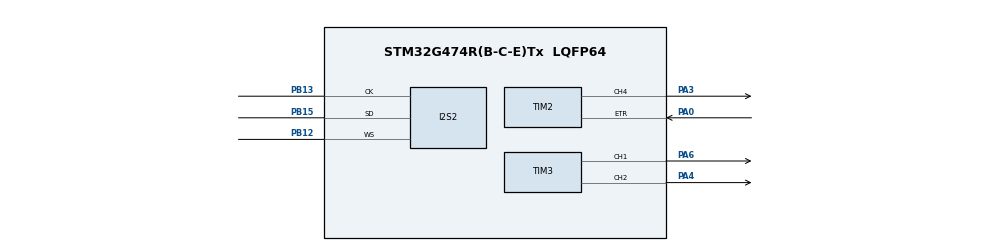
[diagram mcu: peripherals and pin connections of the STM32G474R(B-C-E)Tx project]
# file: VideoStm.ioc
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Dma.Request0=TIM3_CH1
Dma.Request1=TIM3_CH3
Dma.Request2=TIM3_CH4
Dma.Request3=SPI2_TX
Dma.SPI2_TX.3.Direction=DMA_MEMORY_TO_PERIPH
Dma.SPI2_TX.3.EventEnable=DISABLE
Dma.SPI2_TX.3.Instance=DMA1_Channel5
Dma.SPI2_TX.3.MemDataAlignment=DMA_MDATAALIGN_HALFWORD
Dma.SPI2_TX.3.MemInc=DMA_MINC_ENABLE
Dma.SPI2_TX.3.Mode=DMA_CIRCULAR
Dma.SPI2_TX.3.PeriphDataAlignment=DMA_PDATAALIGN_HALFWORD
Dma.SPI2_TX.3.PeriphInc=DMA_PINC_DISABLE
Dma.SPI2_TX.3.Polarity=HAL_DMAMUX_REQ_GEN_RISING
Dma.SPI2_TX.3.Priority=DMA_PRIORITY_HIGH
Dma.SPI2_TX.3.RequestNumber=1
Dma.SPI2_TX.3.SignalID=NONE
Dma.SPI2_TX.3.SyncEnable=DISABLE
Dma.SPI2_TX.3.SyncPolarity=HAL_DMAMUX_SYNC_NO_EVENT
Dma.SPI2_TX.3.SyncRequestNumber=1
Dma.SPI2_TX.3.SyncSignalID=NONE
Dma.TIM3_CH1.0.Direction=DMA_MEMORY_TO_PERIPH
Dma.TIM3_CH1.0.EventEnable=DISABLE
Dma.TIM3_CH1.0.Instance=DMA1_Channel6
Dma.TIM3_CH1.0.MemDataAlignment=DMA_MDATAALIGN_HALFWORD
Dma.TIM3_CH1.0.MemInc=DMA_MINC_ENABLE
Dma.TIM3_CH1.0.Mode=DMA_CIRCULAR
Dma.TIM3_CH1.0.PeriphDataAlignment=DMA_PDATAALIGN_HALFWORD
Dma.TIM3_CH1.0.PeriphInc=DMA_PINC_DISABLE
Dma.TIM3_CH1.0.Polarity=HAL_DMAMUX_REQ_GEN_RISING
Dma.TIM3_CH1.0.Priority=DMA_PRIORITY_MEDIUM
Dma.TIM3_CH1.0.RequestNumber=1
Dma.TIM3_CH1.0.SignalID=NONE
Dma.TIM3_CH1.0.SyncEnable=DISABLE
Dma.TIM3_CH1.0.SyncPolarity=HAL_DMAMUX_SYNC_NO_EVENT
Dma.TIM3_CH1.0.SyncRequestNumber=1
Dma.TIM3_CH1.0.SyncSignalID=NONE
Dma.TIM3_CH3.1.Direction=DMA_MEMORY_TO_PERIPH
Dma.TIM3_CH3.1.EventEnable=DISABLE
Dma.TIM3_CH3.1.Instance=DMA1_Channel2
Dma.TIM3_CH3.1.MemDataAlignment=DMA_MDATAALIGN_WORD
Dma.TIM3_CH3.1.MemInc=DMA_MINC_ENABLE
Dma.TIM3_CH3.1.Mode=DMA_CIRCULAR
Dma.TIM3_CH3.1.PeriphDataAlignment=DMA_PDATAALIGN_WORD
Dma.TIM3_CH3.1.PeriphInc=DMA_PINC_DISABLE
Dma.TIM3_CH3.1.Polarity=HAL_DMAMUX_REQ_GEN_RISING
Dma.TIM3_CH3.1.Priority=DMA_PRIORITY_MEDIUM
Dma.TIM3_CH3.1.RequestNumber=1
Dma.TIM3_CH3.1.SignalID=NONE
Dma.TIM3_CH3.1.SyncEnable=DISABLE
Dma.TIM3_CH3.1.SyncPolarity=HAL_DMAMUX_SYNC_NO_EVENT
Dma.TIM3_CH3.1.SyncRequestNumber=1
Dma.TIM3_CH3.1.SyncSignalID=NONE
Dma.TIM3_CH4.2.Direction=DMA_MEMORY_TO_PERIPH
Dma.TIM3_CH4.2.EventEnable=DISABLE
Dma.TIM3_CH4.2.Instance=DMA1_Channel3
Dma.TIM3_CH4.2.MemDataAlignment=DMA_MDATAALIGN_WORD
Dma.TIM3_CH4.2.MemInc=DMA_MINC_ENABLE
Dma.TIM3_CH4.2.Mode=DMA_CIRCULAR
Dma.TIM3_CH4.2.PeriphDataAlignment=DMA_PDATAALIGN_WORD
Dma.TIM3_CH4.2.PeriphInc=DMA_PINC_DISABLE
Dma.TIM3_CH4.2.Polarity=HAL_DMAMUX_REQ_GEN_RISING
Dma.TIM3_CH4.2.Priority=DMA_PRIORITY_MEDIUM
Dma.TIM3_CH4.2.RequestNumber=1
Dma.TIM3_CH4.2.SignalID=NONE
Dma.TIM3_CH4.2.SyncEnable=DISABLE
Dma.TIM3_CH4.2.SyncPolarity=HAL_DMAMUX_SYNC_NO_EVENT
Dma.TIM3_CH4.2.SyncRequestNumber=1
Dma.TIM3_CH4.2.SyncSignalID=NONE
I2S2.ErrorAudioFreq=- %
I2S2.FullDuplexMode=I2S_FULLDUPLEXMODE_DISABLE
I2S2.Instance=SPI$Index
I2S2.RealAudioFreq=- Hz
I2S2.VirtualMode=I2S_MODE_MASTER
Mcu.Family=STM32G4
Mcu.Name=STM32G474R(B-C-E)Tx
Mcu.Package=LQFP64
NVIC.DMA1_Channel2_IRQn=true\:0\:0\:false\:false\:true\:false\:true\:true
NVIC.DMA1_Channel3_IRQn=true\:0\:0\:false\:false\:true\:false\:true\:true
NVIC.DMA1_Channel5_IRQn=true\:0\:0\:false\:false\:true\:false\:true\:true
NVIC.DMA1_Channel6_IRQn=true\:0\:0\:false\:false\:true\:false\:true\:true
NVIC.PriorityGroup=NVIC_PRIORITYGROUP_4
PA0.Signal=S_TIM2_ETR
PA3.Signal=S_TIM2_CH4
PA4.Signal=S_TIM3_CH2
PA6.Signal=S_TIM3_CH1
PB12.Mode=Half_Duplex_Master
PB12.Signal=I2S2_WS
PB13.Mode=Half_Duplex_Master
PB13.Signal=I2S2_CK
PB15.Mode=Half_Duplex_Master
PB15.Signal=I2S2_SD
PF0-OSC_IN.Mode=HSE-External-Clock-Source
PF0-OSC_IN.Signal=RCC_OSC_IN
ProjectManager.HeapSize=0x200
ProjectManager.StackSize=0x400
ProjectManager.TargetToolchain=STM32CubeIDE
RCC.ADC12Freq_Value=168000000
RCC.ADC345Freq_Value=168000000
RCC.AHBFreq_Value=168000000
RCC.APB1Freq_Value=168000000
RCC.APB1TimFreq_Value=168000000
RCC.APB2Freq_Value=168000000
RCC.APB2TimFreq_Value=168000000
RCC.CortexFreq_Value=168000000
RCC.EXTERNAL_CLOCK_VALUE=12288000
RCC.HCLKFreq_Value=168000000
RCC.HSE_VALUE=8000000
RCC.HSI48_VALUE=48000000
RCC.HSI_VALUE=16000000
RCC.LSE_VALUE=32768
RCC.PLLN=42
RCC.PLLSourceVirtual=RCC_PLLSOURCE_HSE
RCC.SYSCLKFreq_VALUE=168000000
RCC.SYSCLKSource=RCC_SYSCLKSOURCE_PLLCLK
RCC.USBFreq_Value=168000000
RCC.VCOOutputFreq_Value=336000000
SH.S_TIM2_CH4.0=TIM2_CH4,PWM Generation4 CH4
SH.S_TIM2_ETR.0=TIM2_ETR,TriggerSource_ETR
SH.S_TIM3_CH1.0=TIM3_CH1,Output Compare1 CH1
SH.S_TIM3_CH2.0=TIM3_CH2,PWM Generation2 CH2
TIM2.Channel-PWM\ Generation4\ CH4=TIM_CHANNEL_4
TIM2.ClockDivision=TIM_CLOCKDIVISION_DIV2
TIM2.OCPolarity_4=TIM_OCPOLARITY_LOW
TIM2.TIM_MasterOutputTrigger=TIM_TRGO_OC4REF
TIM2.TIM_MasterSlaveMode=TIM_MASTERSLAVEMODE_ENABLE
TIM3.Channel-Output\ Compare1\ CH1=TIM_CHANNEL_1
TIM3.Channel-Output\ Compare3\ No\ Output=TIM_CHANNEL_3
TIM3.Channel-Output\ Compare4\ No\ Output=TIM_CHANNEL_4
TIM3.Channel-PWM\ Generation2\ CH2=TIM_CHANNEL_2
TIM3.OCMode_1=TIM_OCMODE_TOGGLE
TIM3.OCPolarity_1=TIM_OCPOLARITY_LOW
TIM3.OCPolarity_2=TIM_OCPOLARITY_LOW
TIM3.OCPolarity_3=TIM_OCPOLARITY_LOW
TIM3.OCPolarity_4=TIM_OCPOLARITY_LOW
TIM3.PulseNoDither_1=0xffff
TIM3.PulseNoDither_3=208
TIM3.PulseNoDither_4=208+672
VP_SYS_VS_DBSignals.Mode=DisableDeadBatterySignals
VP_TIM2_VS_ClockSourceINT.Mode=Internal
VP_TIM2_VS_ControllerModeTrigger.Mode=Trigger Mode
VP_TIM3_VS_ClockSourceINT.Mode=Internal
VP_TIM3_VS_ClockSourceITR.Mode=TriggerSource_ITR1
VP_TIM3_VS_ControllerModeTrigger.Mode=Trigger Mode
VP_TIM3_VS_no_output3.Mode=Output Compare3 No Output
VP_TIM3_VS_no_output4.Mode=Output Compare4 No Output
board=custom

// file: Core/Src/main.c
/* USER CODE BEGIN Header */
/**
  ******************************************************************************
  * @file           : main.c
  * @brief          : Main program body
  ******************************************************************************
  * @attention
  *
  * Copyright (c) 2025 STMicroelectronics.
  * All rights reserved.
  *
  * This software is licensed under terms that can be found in the LICENSE file
  * in the root directory of this software component.
  * If no LICENSE file comes with this software, it is provided AS-IS.
  *
  ******************************************************************************
  */
/* USER CODE END Header */
#include "main.h"

/* USER CODE BEGIN Includes */
#include "stm32g4xx_hal.h"
#include "video.h"
#include <stdlib.h>
#include <string.h>
#include "stdio.h"

void show(void);
/* USER CODE END Includes */

/* USER CODE BEGIN PD */
//uint16_t fullFrame[TOTAL_LINES * VID_HSIZE];

/* USER CODE END PD */

/* USER CODE BEGIN PM */
//#define DelayMs(ms)  HAL_Delay(ms)

/* USER CODE END PM */

I2S_HandleTypeDef hi2s2;
DMA_HandleTypeDef hdma_spi2_tx;

TIM_HandleTypeDef htim2;
TIM_HandleTypeDef htim3;
DMA_HandleTypeDef hdma_tim3_ch1;
DMA_HandleTypeDef hdma_tim3_ch3;
DMA_HandleTypeDef hdma_tim3_ch4;

/* USER CODE BEGIN PV */
__IO uint32_t Paused;
__IO uint32_t TimingDelay;
/* USER CODE END PV */

void SystemClock_Config(void);
static void MX_GPIO_Init(void);
static void MX_DMA_Init(void);
static void MX_TIM2_Init(void);
static void MX_I2S2_Init(void);
static void MX_TIM3_Init(void);
void Video_AdjustI2SFor8MHz(void);
void Video_SetupTiming(void);

/* USER CODE BEGIN 0 */
void DelayMs(uint32_t nTime) // delay function
{
  TimingDelay = nTime;
  while((TimingDelay != 0));
  while(Paused);
}
void Gpio_deinit(GPIO_TypeDef  *GPIOx){
		for(int i =0; i<15;i++){
			HAL_GPIO_DeInit(GPIOA, i);
		}
	}

void TIMER_SET(uint32_t sys){

	if (sys == 16000000){
		  __HAL_I2S_DISABLE(&hi2s2);
		   SPI2->I2SPR = 1;
		   __HAL_I2S_ENABLE(&hi2s2);
	}

	else if(sys == 48000000){
		  __HAL_I2S_DISABLE(&hi2s2);
		  SPI2->I2SPR = (3 << SPI_I2SPR_I2SDIV_Pos)
		              | (0 << SPI_I2SPR_ODD_Pos);
		   __HAL_I2S_ENABLE(&hi2s2);
	}

	else if (sys == 96000000){
		  __HAL_I2S_DISABLE(&hi2s2);
		  SPI2->I2SPR = (6 << SPI_I2SPR_I2SDIV_Pos)
		              | (0 << SPI_I2SPR_ODD_Pos);
		   __HAL_I2S_ENABLE(&hi2s2);
		   HAL_Delay(1);
	}

	else if(sys == 120000000){
		__HAL_I2S_DISABLE(&hi2s2);
		SPI2->I2SPR = (7 << SPI_I2SPR_I2SDIV_Pos) | (1 << SPI_I2SPR_ODD_Pos);
		__HAL_I2S_ENABLE(&hi2s2);
	}
}

void demo_no_uart_run(void)
{
    /* Clear the screen and reset the cursor to the top left. */
    gdiClearScreen();

    /* List of names to display. */
    const char *names[] = { "Moshe", "Idan", "Lior", "Reut", "Davidi" };
    const int count = sizeof(names) / sizeof(names[0]);

    /* For each name, compute the x coordinate such that the text
     * appears flush to the right edge of the display.  Then set
     * the cursor and print the characters one by one.  After each
     * name, wait for a second. */
    for (int i = 0; i < count; ++i) {
        //int len = strlen(names[i]);
        int x = VID_PIXELS_X/2 - 5 * GDI_SYSFONT_WIDTH;
        int y = i * GDI_SYSFONT_HEIGHT;
        gdiSetCursor(x, y);
        for (const char *p = names[i]; *p; ++p) {
            gdiPutChar((uint8_t)*p);
        }
        /* Delay 1 second (1000 ms) */
        HAL_Delay(1000);
    }
}

void demo_vt100_commands(void)
{
    const char CURSOR_CHAR = '*';  // Visible cursor character

    /* Helper function to print cursor position */
    void print_cursor(void) {
        gdiPutChar(CURSOR_CHAR);
        HAL_Delay(500);  // Show cursor briefly
    }

    /* Clear the screen and reset cursor position */
    vt100_init();
    HAL_Delay(500);

    /* Center position calculation */
    const int center_x = VID_PIXELS_X/2 - 10 * GDI_SYSFONT_WIDTH;
    const int center_y = VID_PIXELS_Y/2 - 5 * GDI_SYSFONT_HEIGHT;

    /* Test 1: Direct cursor positioning */
    gdiSetCursor(center_x, center_y - 3 * GDI_SYSFONT_HEIGHT);
    const char *cmd1 = "Testing ESC[H - Cursor Home";
    for(const char *p = cmd1; *p; p++) {
        gdiPutChar(*p);
    }
    HAL_Delay(1000);
    vt100_process_buffer((const uint8_t*)"\x1B[H", 3); // Move cursor to home
    print_cursor();
    HAL_Delay(1000);

    /* Test 2: Clear screen */
    gdiSetCursor(center_x, center_y - 2 * GDI_SYSFONT_HEIGHT);
    const char *cmd2 = "Testing ESC[2J - Clear Screen";
    for(const char *p = cmd2; *p; p++) {
        gdiPutChar(*p);
    }
    HAL_Delay(1000);
    vt100_process_buffer((const uint8_t*)"\x1B[2J", 4);
    print_cursor();
    HAL_Delay(1000);

    /* Test 3: Cursor movement up */
    gdiSetCursor(center_x, center_y);
    const char *cmd3 = "Testing ESC[A - Cursor Up";
    for(const char *p = cmd3; *p; p++) {
        gdiPutChar(*p);
    }
    HAL_Delay(1000);
    vt100_process_buffer((const uint8_t*)"\x1B[2A", 4); // Move up 2 lines
    print_cursor();
    HAL_Delay(1000);

    /* Test 4: Cursor movement down */
    gdiSetCursor(center_x, center_y);
    const char *cmd4 = "Testing ESC[B - Cursor Down";
    for(const char *p = cmd4; *p; p++) {
        gdiPutChar(*p);
    }
    HAL_Delay(1000);
    vt100_process_buffer((const uint8_t*)"\x1B[2B", 4); // Move down 2 lines
    print_cursor();
    HAL_Delay(1000);

    /* Test 5: Cursor movement right */
    gdiSetCursor(center_x, center_y);
    const char *cmd5 = "Testing ESC[C - Cursor Right";
    for(const char *p = cmd5; *p; p++) {
        gdiPutChar(*p);
    }
    HAL_Delay(1000);
    vt100_process_buffer((const uint8_t*)"\x1B[5C", 4); // Move right 5 chars
    print_cursor();
    HAL_Delay(1000);

    /* Test 6: Cursor movement left */
    gdiSetCursor(center_x, center_y);
    const char *cmd6 = "Testing ESC[D - Cursor Left";
    for(const char *p = cmd6; *p; p++) {
        gdiPutChar(*p);
    }
    HAL_Delay(1000);
    vt100_process_buffer((const uint8_t*)"\x1B[5D", 4); // Move left 5 chars
    print_cursor();
    HAL_Delay(1000);

    /* Test 7: Absolute cursor positioning */
    gdiSetCursor(center_x, center_y);
    const char *cmd7 = "Testing ESC[row;colH - Absolute Position";
    for(const char *p = cmd7; *p; p++) {
        gdiPutChar(*p);
    }
    HAL_Delay(1000);
    vt100_process_buffer((const uint8_t*)"\x1B[12;40H", 8); // Move to row 12, col 40
    print_cursor();
    HAL_Delay(1000);

    /* Final message */
    vt100_process_buffer((const uint8_t*)"\x1B[2J", 4); // Clear screen
    gdiSetCursor(center_x, center_y);
    const char *final = "VT100 Command Demo Complete!";
    for(const char *p = final; p++;) {
        gdiPutChar(*p);
    }
    HAL_Delay(2000);
}

/* USER CODE END 0 */

int main(void)
{

  /* MCU Configuration--------------------------------------------------------*/

  /* Reset of all peripherals, Initializes the Flash interface and the Systick. */
	HAL_Init();

  /* USER CODE BEGIN Init */
	HAL_I2S_DeInit(&hi2s2);
	HAL_TIM_OC_DeInit(&htim2);
	HAL_TIM_OC_DeInit(&htim3);
	Gpio_deinit(GPIOA);
	Gpio_deinit(GPIOB);
	Gpio_deinit(GPIOC);
	HAL_DMA_DeInit(&hdma_tim3_ch1);
	HAL_DMA_DeInit(&hdma_tim3_ch3);
	HAL_DMA_DeInit(&hdma_spi2_tx);
	HAL_DMA_DeInit(&hdma_tim3_ch4);
  /* --- Enable Flash prefetch and caches before changing SYSCLK --- */
  __HAL_FLASH_PREFETCH_BUFFER_ENABLE();
  __HAL_FLASH_INSTRUCTION_CACHE_ENABLE();
  __HAL_FLASH_DATA_CACHE_ENABLE();
  /* USER CODE END Init */

  /* Configure the system clock */
  SystemClock_Config();

  /* Initialize all configured peripherals */
  MX_GPIO_Init();
  MX_DMA_Init();
  MX_TIM2_Init();
  MX_I2S2_Init();
  TIMER_SET(HAL_RCC_GetSysClockFreq());
  MX_TIM3_Init();
  /* USER CODE BEGIN 2 */

  //Video_AdjustI2SFor8MHz();
  //Video_SetupTiming();
  // 1) How many timer ticks per half-word at your clock?

  //do know if it is necessary
  HAL_TIM_Base_Start(&htim2); // start the timer for the video sync

  //HAL_TIM_OC_Start(&htim2, TIM_CHANNEL_4);  // OC4Ref → TRGO

  HAL_TIM_OC_Start(&htim3, TIM_CHANNEL_1);
  HAL_TIM_PWM_Start(&htim3, TIM_CHANNEL_2); // this the same
  //HAL_TIM_OC_Start(&htim3, TIM_CHANNEL_3);
  HAL_TIM_OC_Start(&htim3, TIM_CHANNEL_4);

  //AL_Delay(9);
//
//  HAL_DMA_Start(
//    &hdma_tim3_ch1,
//    (uint32_t)SyncTable,                // memory: array of CCR1 timings
//    (uint32_t)&TIM3->CCR1,              // peripheral: CCR1 register
//	VID_VSIZE                         // one entry per visible line
//  );
//  __HAL_TIM_ENABLE_DMA(&htim3, TIM_DMA_CC1);  // also enable CC1DE for VSync

  //HAL_Delay(1);

  // 2) LINE BUFFERS → I2S DMA CMAR at back porch (CC3)
  HAL_DMA_Start(
    &hdma_tim3_ch3,
    (uint32_t)lineptrs,                 // memory: array of line-buffer addresses
    (uint32_t)&hdma_spi2_tx.Instance->CMAR,
	VID_VSIZE//VID_VSIZE
  );

//  // 3) BLACK-PORCH → I2S DMA CMAR at front porch (CC4)
//  HAL_DMA_Start(
//    &hdma_tim3_ch4,
//    (uint32_t)borders,                  // memory: single-entry blank-line buffer
//    (uint32_t)&hdma_spi2_tx.Instance->CMAR,
//    VID_VSIZE// one entry per line
//  );

  // 4) Kick off the I2S DMA stream once
  HAL_I2S_Transmit_DMA(
    &hi2s2,
    (uint16_t*)SyncTable,
    VID_HSIZE// 21 + 11 = 32 half-words per line
  );

  // also i added a function for handleing
  //srand(SysTick->VAL);

  /* USER CODE END 2 */

  /* Infinite loop */
  /* USER CODE BEGIN WHILE */
  //vidClearScreen();
//  gdiDrawTextEx(60, 10, "Hello World!");
//  gdiDrawTextEx(110, 60, "hey");
//  gdiDrawTextEx(120, 70, "MOSHE");
//  gdiDrawTextEx(130, 55, "REUT");
  //gdiDrawTextEx(140, 90, "IDAN");
//  gdiDrawTextEx(150, 80, "RUBEN");
//  gdiDrawTextEx(160, 100, "a");

  //static uint8_t rx_byte;
  vt100_init();
  //HAL_Delay(1);

  while (1)
  {
	  demo_vt100_commands();
	  HAL_Delay(1000);
    /* USER CODE END WHILE */

  }
}

void SystemClock_Config(void)
{
  RCC_OscInitTypeDef RCC_OscInitStruct = {0};
  RCC_ClkInitTypeDef RCC_ClkInitStruct = {0};

  /** Configure the main internal regulator output voltage
  */
  HAL_PWREx_ControlVoltageScaling(PWR_REGULATOR_VOLTAGE_SCALE1);

  /** Initializes the RCC Oscillators according to the specified parameters
  * in the RCC_OscInitTypeDef structure.
  */
  RCC_OscInitStruct.OscillatorType = RCC_OSCILLATORTYPE_HSE;
  RCC_OscInitStruct.HSEState = RCC_HSE_BYPASS;
  RCC_OscInitStruct.PLL.PLLState = RCC_PLL_ON;
  RCC_OscInitStruct.PLL.PLLSource = RCC_PLLSOURCE_HSE;
  RCC_OscInitStruct.PLL.PLLM = RCC_PLLM_DIV1;
  RCC_OscInitStruct.PLL.PLLN = 30;
  RCC_OscInitStruct.PLL.PLLP = RCC_PLLP_DIV10;
  RCC_OscInitStruct.PLL.PLLQ = RCC_PLLQ_DIV8;
  RCC_OscInitStruct.PLL.PLLR = RCC_PLLR_DIV2;
  if (HAL_RCC_OscConfig(&RCC_OscInitStruct) != HAL_OK)
  {
    Error_Handler();
  }

  // 8mhz *12 / 2

  /** Initializes the CPU, AHB and APB buses clocks
  */
  RCC_ClkInitStruct.ClockType = RCC_CLOCKTYPE_HCLK|RCC_CLOCKTYPE_SYSCLK
                              |RCC_CLOCKTYPE_PCLK1|RCC_CLOCKTYPE_PCLK2;
  RCC_ClkInitStruct.SYSCLKSource = RCC_SYSCLKSOURCE_PLLCLK;
  RCC_ClkInitStruct.AHBCLKDivider = RCC_SYSCLK_DIV1;
  RCC_ClkInitStruct.APB1CLKDivider = RCC_HCLK_DIV1;
  RCC_ClkInitStruct.APB2CLKDivider = RCC_HCLK_DIV1;

  if (HAL_RCC_ClockConfig(&RCC_ClkInitStruct, FLASH_LATENCY_5) != HAL_OK)
  {
    Error_Handler();
  }
}

static void MX_I2S2_Init(void)
{

  /* USER CODE BEGIN I2S2_Init 1 */
	//hi2s2.Init.CPOL = I2S_CPOL_HIGH;

  /* USER CODE END I2S2_Init 1 */
  hi2s2.Instance = SPI2;
  hi2s2.Init.Mode = I2S_MODE_MASTER_TX;
  hi2s2.Init.Standard = I2S_STANDARD_PHILIPS;
  hi2s2.Init.DataFormat = I2S_DATAFORMAT_16B;
  hi2s2.Init.MCLKOutput = I2S_MCLKOUTPUT_DISABLE;
  hi2s2.Init.AudioFreq = I2S_AUDIOFREQ_8K;
  hi2s2.Init.CPOL = I2S_CPOL_HIGH;
  if (HAL_I2S_Init(&hi2s2) != HAL_OK)
  {
    Error_Handler();
  }
  /* USER CODE BEGIN I2S2_Init 2 */
//  __HAL_I2S_DISABLE(&hi2s2);
////  SPI2->I2SPR = (3 << SPI_I2SPR_I2SDIV_Pos)
////              | (0 << SPI_I2SPR_ODD_Pos);
//
//   SPI2->I2SPR = 1;   // I2SDIV = 1, ODD = 0
//   __HAL_I2S_ENABLE(&hi2s2);

  /* USER CODE END I2S2_Init 2 */

}

static void MX_TIM2_Init(void)
{

  TIM_ClockConfigTypeDef sClockSourceConfig = {0};
  TIM_SlaveConfigTypeDef sSlaveConfig = {0};
  TIM_MasterConfigTypeDef sMasterConfig = {0};
  TIM_OC_InitTypeDef sConfigOC = {0};

  /* USER CODE BEGIN TIM2_Init 1 */

  //i should change :
  //htim2.Init.Prescaler         = VID_HSIZE/4 - 1; // 32/4 -1 = 7
  //htim2.Init.Period            = 2*VID_VSIZE - 1; // 2*625-1 = 1249
  //sConfigOC.Pulse      = VID_VSIZE - 1;

  /* USER CODE END TIM2_Init 1 */
  htim2.Instance = TIM2;
  htim2.Init.Prescaler = VID_HSIZE/4 - 1; // 32/4 -1 = 7
  htim2.Init.CounterMode = TIM_COUNTERMODE_UP;
  htim2.Init.Period = 2*VID_VSIZE - 1; // 2*625-1 = 1249
  htim2.Init.ClockDivision = TIM_CLOCKDIVISION_DIV2;
  htim2.Init.AutoReloadPreload = TIM_AUTORELOAD_PRELOAD_DISABLE;
  if (HAL_TIM_Base_Init(&htim2) != HAL_OK)
  {
    Error_Handler();
  }
  sClockSourceConfig.ClockSource = TIM_CLOCKSOURCE_ETRMODE1;
  if (HAL_TIM_ConfigClockSource(&htim2, &sClockSourceConfig) != HAL_OK)
  {
    Error_Handler();
  }
  if (HAL_TIM_PWM_Init(&htim2) != HAL_OK)
  {
    Error_Handler();
  }
  sSlaveConfig.SlaveMode = TIM_SLAVEMODE_TRIGGER;//NEEDS TO BE CHECK WITH EXTERNAL1
  sSlaveConfig.InputTrigger = TIM_TS_ETRF;
  sSlaveConfig.TriggerPolarity = TIM_TRIGGERPOLARITY_NONINVERTED;
  sSlaveConfig.TriggerPrescaler = TIM_TRIGGERPRESCALER_DIV1;
  sSlaveConfig.TriggerFilter = 0;
  if (HAL_TIM_SlaveConfigSynchro(&htim2, &sSlaveConfig) != HAL_OK)
  {
    Error_Handler();
  }
  sMasterConfig.MasterOutputTrigger = TIM_TRGO_OC4REF; // OC4Ref → TRGO;
  sMasterConfig.MasterSlaveMode = TIM_MASTERSLAVEMODE_ENABLE;
  if (HAL_TIMEx_MasterConfigSynchronization(&htim2, &sMasterConfig) != HAL_OK)
  {
    Error_Handler();
  }
  sConfigOC.OCMode = TIM_OCMODE_PWM1;
  sConfigOC.Pulse =  VID_VSIZE - 1;
  sConfigOC.OCPolarity = TIM_OCPOLARITY_LOW;
  sConfigOC.OCFastMode = TIM_OCFAST_DISABLE;
  if (HAL_TIM_PWM_ConfigChannel(&htim2, &sConfigOC, TIM_CHANNEL_4) != HAL_OK)
  {
    Error_Handler();
  }
  HAL_TIM_MspPostInit(&htim2);

}

static void MX_TIM3_Init(void)
{

  TIM_ClockConfigTypeDef sClockSourceConfig = {0};
  TIM_SlaveConfigTypeDef sSlaveConfig = {0};
  TIM_MasterConfigTypeDef sMasterConfig = {0};
  TIM_OC_InitTypeDef sConfigOC = {0};

  /* USER CODE BEGIN TIM3_Init 1 */
  //need to change
  //htim3.Init.Period = TIMERCOUNTS - 1;  // e.g. 1023 for a 1024-count line

  //FOR CHANNEL 1 :
  //sConfigOC.Pulse = NO_TOG;

  //FOR CHANNEL 2:
  //sConfigOC.Pulse = HSYNCCOUNTS;

  /* USER CODE END TIM3_Init 1 */
  htim3.Instance = TIM3;
  htim3.Init.Prescaler = 0;
  htim3.Init.CounterMode = TIM_COUNTERMODE_UP;
  htim3.Init.Period = TIMERCOUNTS - 1;
  htim3.Init.ClockDivision = TIM_CLOCKDIVISION_DIV1;
  htim3.Init.AutoReloadPreload = TIM_AUTORELOAD_PRELOAD_DISABLE;
  if (HAL_TIM_Base_Init(&htim3) != HAL_OK)
  {
    Error_Handler();
  }
  sClockSourceConfig.ClockSource = TIM_CLOCKSOURCE_INTERNAL;
  if (HAL_TIM_ConfigClockSource(&htim3, &sClockSourceConfig) != HAL_OK)
  {
    Error_Handler();
  }
  if (HAL_TIM_OC_Init(&htim3) != HAL_OK)
  {
    Error_Handler();
  }
  if (HAL_TIM_PWM_Init(&htim3) != HAL_OK)
  {
    Error_Handler();
  }
  sSlaveConfig.SlaveMode = TIM_SLAVEMODE_TRIGGER;
  sSlaveConfig.InputTrigger = TIM_TS_ITR1;
  if (HAL_TIM_SlaveConfigSynchro(&htim3, &sSlaveConfig) != HAL_OK)
  {
    Error_Handler();
  }
  sMasterConfig.MasterOutputTrigger = TIM_TRGO_RESET;
  sMasterConfig.MasterSlaveMode = TIM_MASTERSLAVEMODE_ENABLE;
  if (HAL_TIMEx_MasterConfigSynchronization(&htim3, &sMasterConfig) != HAL_OK)
  {
    Error_Handler();
  }
  sConfigOC.OCMode = TIM_OCMODE_TOGGLE;
  sConfigOC.Pulse = NO_TOG;
  sConfigOC.OCPolarity = TIM_OCPOLARITY_LOW;
  sConfigOC.OCFastMode = TIM_OCFAST_DISABLE;
  if (HAL_TIM_OC_ConfigChannel(&htim3, &sConfigOC, TIM_CHANNEL_1) != HAL_OK)
  {
    Error_Handler();
  }
  sConfigOC.OCMode = TIM_OCMODE_PWM1;
  sConfigOC.Pulse = HSYNCCOUNTS;//HSYNCCOUNTS;
  if (HAL_TIM_PWM_ConfigChannel(&htim3, &sConfigOC, TIM_CHANNEL_2) != HAL_OK)
  {
    Error_Handler();
  }
  sConfigOC.OCMode = TIM_OCMODE_TIMING;
  sConfigOC.Pulse = 1100;//208;
  if (HAL_TIM_OC_ConfigChannel(&htim3, &sConfigOC, TIM_CHANNEL_3) != HAL_OK)
  {
    Error_Handler();
  }
  sConfigOC.Pulse = 7300;//(672+208);//(672+208);
  if (HAL_TIM_OC_ConfigChannel(&htim3, &sConfigOC, TIM_CHANNEL_4) != HAL_OK)
  {
    Error_Handler();
  }
  /* USER CODE BEGIN TIM3_Init 2 */
  //TIM_DMACmd(TIM3, TIM_DMA_CC1|TIM_DMA_CC3, ENABLE);
  /* USER CODE END TIM3_Init 2 */
  HAL_TIM_MspPostInit(&htim3);
  /* Allow TIM3 Compare-3 (CC3) and Compare-4 (CC4) events to generate DMA requests */
  //__HAL_TIM_ENABLE_DMA(&htim3, TIM_DMA_CC2);
  __HAL_TIM_ENABLE_DMA(&htim3, TIM_DMA_CC3);   // CC3DE bit → DMA request on CC3
  __HAL_TIM_ENABLE_DMA(&htim3, TIM_DMA_CC4);   // CC4DE bit → DMA request on CC4
  //__HAL_TIM_ENABLE_OCxPRELOAD(&htim3, TIM_CHANNEL_3);
  //__HAL_TIM_ENABLE_OCxPRELOAD(&htim3, TIM_CHANNEL_4);

}

static void MX_DMA_Init(void)
{

  /* DMA controller clock enable */
  __HAL_RCC_DMAMUX1_CLK_ENABLE();
  __HAL_RCC_DMA1_CLK_ENABLE();

  /* DMA interrupt init */
  /* DMA1_Channel2_IRQn interrupt configuration */
  HAL_NVIC_SetPriority(DMA1_Channel2_IRQn, 0, 0);
  HAL_NVIC_EnableIRQ(DMA1_Channel2_IRQn);
  /* DMA1_Channel3_IRQn interrupt configuration */
  HAL_NVIC_SetPriority(DMA1_Channel3_IRQn, 0, 0);
  HAL_NVIC_EnableIRQ(DMA1_Channel3_IRQn);
  /* DMA1_Channel5_IRQn interrupt configuration */
  HAL_NVIC_SetPriority(DMA1_Channel5_IRQn, 0, 0);
  HAL_NVIC_EnableIRQ(DMA1_Channel5_IRQn);
  /* DMA1_Channel6_IRQn interrupt configuration */
  HAL_NVIC_SetPriority(DMA1_Channel6_IRQn, 0, 0);
  HAL_NVIC_EnableIRQ(DMA1_Channel6_IRQn);

}

static void MX_GPIO_Init(void)
{

  /* GPIO Ports Clock Enable */
  __HAL_RCC_GPIOF_CLK_ENABLE();
  __HAL_RCC_GPIOA_CLK_ENABLE();
  __HAL_RCC_GPIOB_CLK_ENABLE();

}

/* USER CODE BEGIN 4 */
void Video_AdjustI2SFor8MHz(void) {
    uint32_t sysclk = HAL_RCC_GetSysClockFreq();      // e.g. 96000000
    uint32_t div    = sysclk / (2 * 8000000UL);       // floor(96e6/16e6) = 6
    uint32_t rem    = sysclk % (2 * 8000000UL);
    uint32_t odd    = (rem != 0);                     // only if you need sub‑pixel accuracy
    SPI2->I2SPR = (div << SPI_I2SPR_I2SDIV_Pos)
                | (odd << SPI_I2SPR_ODD_Pos);
}

//void Video_SetupTiming(void) {
//    uint32_t sys = HAL_RCC_GetSysClockFreq();     // e.g. 96000000
//    uint32_t hf = 1000000UL / PAL_Hsyncinterval;  // 15625
//    uint32_t cnt = sys / hf;                      // 6144 ticks/line
//    uint32_t sync = cnt * PAL_HsyncPulsewidth / PAL_Hsyncinterval; // ~451
//    uint32_t perHW = cnt / VID_HSIZE;             // ticks per half‑word
//
//    __HAL_TIM_SET_AUTORELOAD(&htim3, cnt - 1);
//    __HAL_TIM_SET_COMPARE (&htim3, TIM_CHANNEL_2, sync);
//    __HAL_TIM_SET_COMPARE (&htim3, TIM_CHANNEL_3,
//                           sync + HPORCH*perHW);
//    __HAL_TIM_SET_COMPARE (&htim3, TIM_CHANNEL_4,
//                           sync + (HPORCH+XFERS_PERLINE)*perHW);
//
//}

/* USER CODE END 4 */

void Error_Handler(void)
{
  __disable_irq();
  while (1)
  {
  }
}
